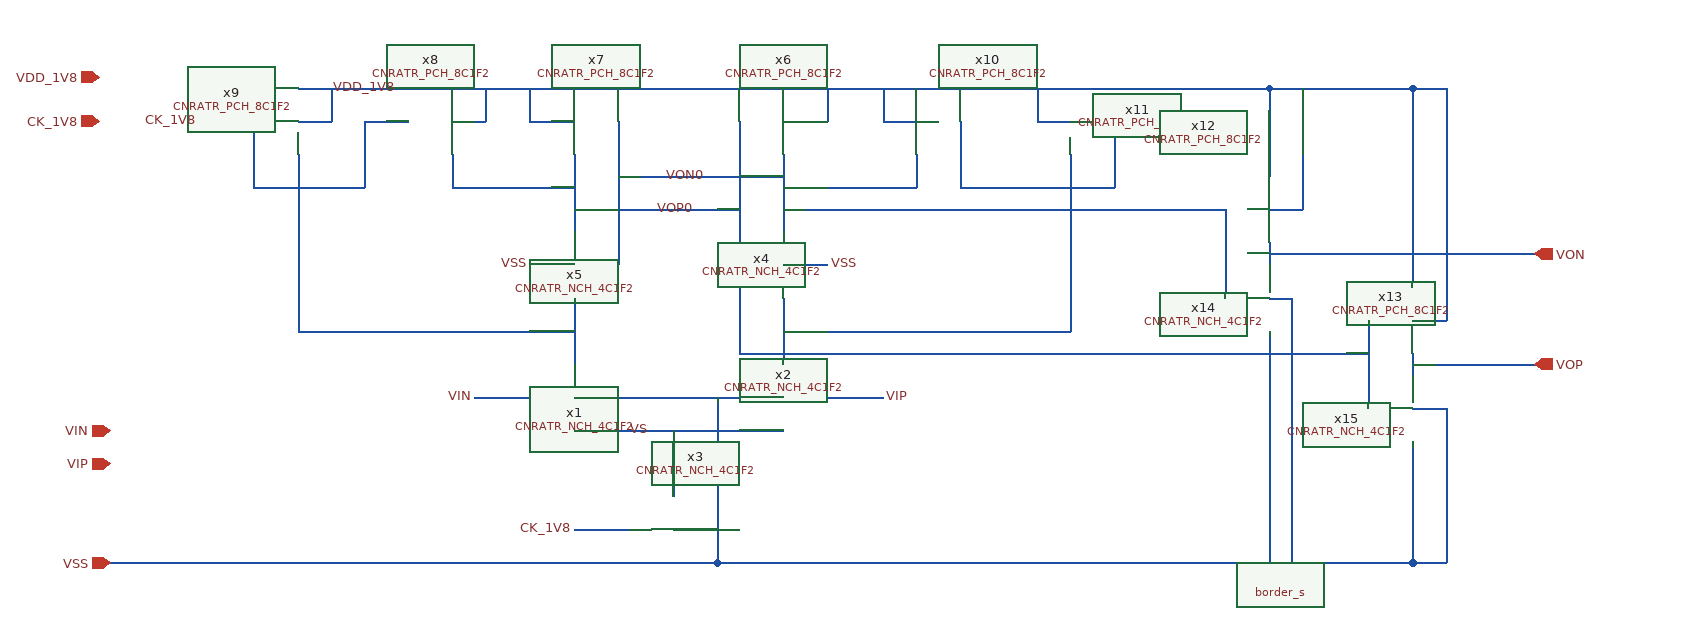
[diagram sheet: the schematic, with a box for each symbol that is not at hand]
v {xschem version=3.4.4 file_version=1.2
}
G {}
K {}
V {}
S {}
E {}
N 590 -400 590 -340 {
lab=#net1}
N 780 -400 780 -340 {
lab=#net2}
N 590 -280 780 -280 {
lab=VS}
N 680 -280 680 -220 {
lab=VS}
N 590 -310 780 -310 {
lab=VSS}
N 680 -160 720 -160 {
lab=VSS}
N 720 -310 720 -160 {
lab=VSS}
N 680 -190 720 -190 {
lab=VSS}
N 630 -560 630 -430 {
lab=VON0}
N 740 -560 740 -430 {
lab=VOP0}
N 780 -530 780 -460 {
lab=VON0}
N 590 -530 590 -460 {
lab=VOP0}
N 590 -480 740 -480 {
lab=VOP0}
N 630 -510 780 -510 {
lab=VON0}
N 340 -590 480 -590 {
lab=VDD_1V8}
N 480 -590 590 -590 {
lab=VDD_1V8}
N 590 -590 780 -590 {
lab=VDD_1V8}
N 780 -590 900 -590 {
lab=VDD_1V8}
N 900 -590 1040 -590 {
lab=VDD_1V8}
N 870 -560 900 -560 {
lab=VDD_1V8}
N 870 -590 870 -560 {
lab=VDD_1V8}
N 340 -530 340 -370 {
lab=#net1}
N 340 -370 590 -370 {
lab=#net1}
N 480 -530 480 -500 {
lab=VOP0}
N 480 -500 590 -500 {
lab=VOP0}
N 900 -530 900 -500 {
lab=VON0}
N 780 -500 900 -500 {
lab=VON0}
N 1040 -530 1040 -370 {
lab=#net2}
N 780 -370 1040 -370 {
lab=#net2}
N 780 -430 820 -430 {
lab=VSS}
N 550 -430 590 -430 {
lab=VSS}
N 550 -560 590 -560 {
lab=VDD_1V8}
N 550 -590 550 -560 {
lab=VDD_1V8}
N 780 -560 820 -560 {
lab=VDD_1V8}
N 820 -590 820 -560 {
lab=VDD_1V8}
N 1010 -560 1040 -560 {
lab=VDD_1V8}
N 1010 -590 1010 -560 {
lab=VDD_1V8}
N 340 -560 370 -560 {
lab=VDD_1V8}
N 370 -590 370 -560 {
lab=VDD_1V8}
N 400 -560 440 -560 {
lab=CK_1V8}
N 400 -560 400 -500 {
lab=CK_1V8}
N 300 -500 400 -500 {
lab=CK_1V8}
N 300 -560 300 -500 {
lab=CK_1V8}
N 250 -560 300 -560 {
lab=CK_1V8}
N 940 -560 940 -500 {
lab=CK_1V8}
N 940 -500 1080 -500 {
lab=CK_1V8}
N 1080 -560 1080 -500 {
lab=CK_1V8}
N 1080 -560 1120 -560 {
lab=CK_1V8}
N 590 -190 640 -190 {
lab=CK_1V8}
N 170 -160 680 -160 {
lab=VSS}
N 500 -310 550 -310 {
lab=VIN}
N 820 -310 870 -310 {
lab=VIP}
N 1220 -590 1220 -510 {
lab=VDD_1V8}
N 1040 -590 1220 -590 {
lab=VDD_1V8}
N 1350 -590 1350 -410 {
lab=VDD_1V8}
N 1220 -590 1350 -590 {
lab=VDD_1V8}
N 1220 -480 1250 -480 {
lab=VDD_1V8}
N 1250 -590 1250 -480 {
lab=VDD_1V8}
N 1350 -380 1380 -380 {
lab=VDD_1V8}
N 1380 -590 1380 -380 {
lab=VDD_1V8}
N 1350 -590 1380 -590 {
lab=VDD_1V8}
N 1220 -450 1220 -430 {
lab=VON}
N 1350 -350 1350 -330 {
lab=VOP}
N 1310 -380 1310 -300 {
lab=VON0}
N 1180 -480 1180 -400 {
lab=VON0}
N 780 -480 1180 -480 {
lab=VON0}
N 720 -160 1350 -160 {
lab=VSS}
N 1350 -260 1350 -160 {
lab=VSS}
N 1350 -270 1350 -260 {
lab=VSS}
N 1350 -300 1380 -300 {
lab=VSS}
N 1380 -300 1380 -160 {
lab=VSS}
N 1350 -160 1380 -160 {
lab=VSS}
N 1220 -370 1220 -160 {
lab=VSS}
N 1220 -400 1240 -400 {
lab=VSS}
N 1240 -400 1240 -160 {
lab=VSS}
N 900 -350 1310 -350 {
lab=VON0}
N 1220 -440 1460 -440 {
lab=VON}
N 1350 -340 1460 -340 {
lab=VOP}
N 480 -560 510 -560 {
lab=VDD_1V8}
N 510 -590 510 -560 {
lab=VDD_1V8}
N 740 -430 740 -350 {}
N 740 -350 900 -350 {}
C {CNR_ATR_SKY130NM/CNRATR_NCH_4C1F2.sym} 550 -310 0 0 {name=x1 }
C {CNR_ATR_SKY130NM/CNRATR_NCH_4C1F2.sym} 820 -310 0 1 {name=x2 }
C {CNR_ATR_SKY130NM/CNRATR_NCH_4C1F2.sym} 640 -190 0 0 {name=x3 }
C {CNR_ATR_SKY130NM/CNRATR_NCH_4C1F2.sym} 740 -430 0 0 {name=x4 }
C {CNR_ATR_SKY130NM/CNRATR_NCH_4C1F2.sym} 630 -430 0 1 {name=x5 }
C {CNR_ATR_SKY130NM/CNRATR_PCH_8C1F2.sym} 740 -560 0 0 {name=x6 }
C {CNR_ATR_SKY130NM/CNRATR_PCH_8C1F2.sym} 630 -560 0 1 {name=x7 }
C {CNR_ATR_SKY130NM/CNRATR_PCH_8C1F2.sym} 440 -560 0 0 {name=x8 }
C {CNR_ATR_SKY130NM/CNRATR_PCH_8C1F2.sym} 300 -560 0 0 {name=x9 }
C {CNR_ATR_SKY130NM/CNRATR_PCH_8C1F2.sym} 940 -560 0 1 {name=x10 }
C {CNR_ATR_SKY130NM/CNRATR_PCH_8C1F2.sym} 1080 -560 0 1 {name=x11 }
C {devices/lab_wire.sym} 250 -560 0 0 {name=p1 sig_type=std_logic lab=CK_1V8}
C {devices/lab_wire.sym} 1120 -560 0 1 {name=p2 sig_type=std_logic lab=CK_1V8}
C {devices/ipin.sym} 160 -600 0 0 {name=p3 lab=VDD_1V8}
C {devices/ipin.sym} 160 -560 0 0 {name=p4 lab=CK_1V8}
C {devices/lab_wire.sym} 590 -190 0 0 {name=p5 sig_type=std_logic lab=CK_1V8}
C {devices/ipin.sym} 170 -280 0 0 {name=p6 lab=VIN}
C {devices/ipin.sym} 170 -250 0 0 {name=p7 lab=VIP}
C {devices/ipin.sym} 170 -160 0 0 {name=p8 lab=VSS}
C {devices/lab_wire.sym} 500 -310 0 0 {name=p9 sig_type=std_logic lab=VIN}
C {devices/lab_wire.sym} 870 -310 0 1 {name=p10 sig_type=std_logic lab=VIP}
C {devices/lab_wire.sym} 820 -430 0 1 {name=p11 sig_type=std_logic lab=VSS}
C {devices/lab_wire.sym} 550 -430 0 0 {name=p12 sig_type=std_logic lab=VSS}
C {CNR_ATR_SKY130NM/CNRATR_PCH_8C1F2.sym} 1180 -480 0 0 {name=x12 }
C {CNR_ATR_SKY130NM/CNRATR_PCH_8C1F2.sym} 1310 -380 0 0 {name=x13 }
C {CNR_ATR_SKY130NM/CNRATR_NCH_4C1F2.sym} 1180 -400 0 0 {name=x14 }
C {CNR_ATR_SKY130NM/CNRATR_NCH_4C1F2.sym} 1310 -300 0 0 {name=x15 }
C {devices/opin.sym} 1460 -340 0 0 {name=p13 lab=VOP}
C {devices/opin.sym} 1460 -440 0 0 {name=p14 lab=VON}
C {cborder/border_s.sym} 1250 -170 0 0 {
user="wulff"
company="wulff"}
C {devices/lab_wire.sym} 430 -590 0 0 {name=p15 sig_type=std_logic lab=VDD_1V8}
C {devices/lab_wire.sym} 700 -480 0 0 {name=p16 sig_type=std_logic lab=VOP0}
C {devices/lab_wire.sym} 710 -510 0 0 {name=p17 sig_type=std_logic lab=VON0}
C {devices/lab_wire.sym} 660 -280 0 0 {name=p18 sig_type=std_logic lab=VS}
